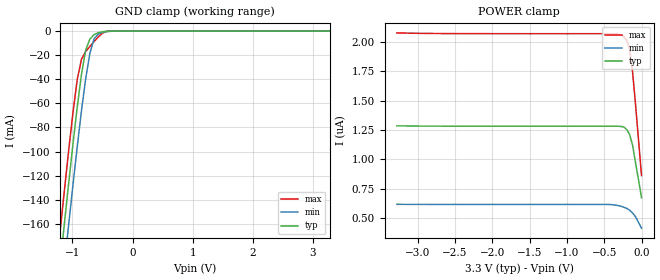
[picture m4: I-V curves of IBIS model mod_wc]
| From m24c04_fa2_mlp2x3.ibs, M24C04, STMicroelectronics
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|   Model mod_wc
[Model]   mod_wc
Model_type Input
Vinl   =   1.000V
Vinh   =   2.300V
C_comp   1.763pF   1.683pF   1.933pF
[Temperature Range]  25.0000   85.0000   -40.0000
[Voltage Range]   3.3000V   2.7000V   3.6000V
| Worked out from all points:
|   GND clamp passes 1 mA (typ) near -0.54 V on its own axis
[GND_clamp]
|Voltage   I(typ)   I(min)   I(max)
-3.3V     -1.254A    -1.285A    -1.23A
-1.27V    -225.1mA   -259.5mA   -197.7mA
-1.2V     -191.1mA   -225.7mA   -163.7mA
-1.13V    -157.7mA   -192.2mA   -130.2mA
-1.06V    -124.9mA   -159.2mA   -97.74mA
-920mV    -62.84mA   -95.74mA   -40.11mA
-850mV    -35.89mA   -66.17mA   -23.29mA
-780mV    -15.88mA   -39.51mA   -17.03mA
-710mV    -6.558mA   -18.36mA   -12.75mA
-640mV    -3.016mA   -6.443mA   -8.697mA
-360mV    -24uA      -153.5uA   -7.885uA
3.28V     528.3pA    6.354nA    369.1pA
[POWER_clamp]
|Voltage   I(typ)   I(min)   I(max)
-3.28V    1.285uA    617.9nA    2.075uA
-2.48V    1.282uA    616.9nA    2.069uA
-440mV    1.282uA    616.6nA    2.069uA
-360mV    1.282uA    611.7nA    2.069uA
-280mV    1.28uA     602.2nA    2.06uA
-240mV    1.276uA    594nA      2.046uA
-200mV    1.255uA    584nA      2.013uA
-160mV    1.213uA    567.6nA    1.938uA
-120mV    1.121uA    544nA      1.743uA
-80mV     969.5nA    512.2nA    1.465uA
-40mV     826nA      464nA      1.165uA
0V        673.3nA    415nA      862.1nA
